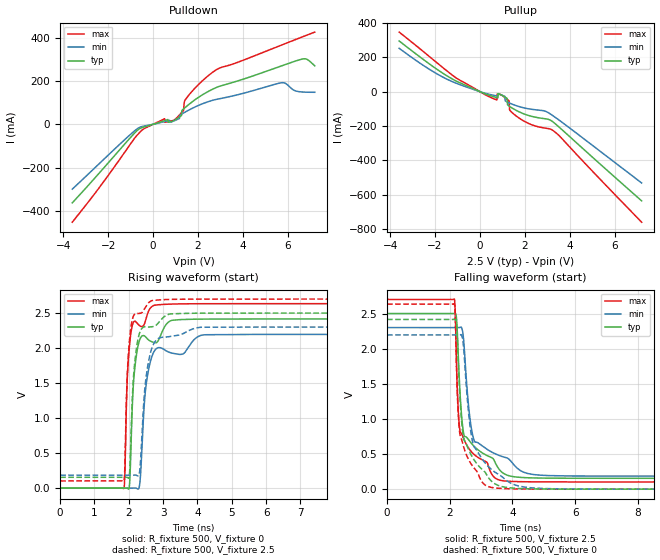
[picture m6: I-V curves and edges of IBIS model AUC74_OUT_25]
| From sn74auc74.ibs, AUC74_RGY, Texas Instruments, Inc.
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[Model]   AUC74_OUT_25
Model_type  Output
Vref =   0
Rref =   500
Cref =   30p
Vmeas =   1.25
| variable   typ   min   max
C_comp   7.89pF   NA   NA
| C_pullup   8.59pF   0.39pF   24.21pF
| C_pulldown   7.03pF   1.93pF   16.23pF
[Temperature Range]   40   100   -40
| Ambient temperature   25   85   -40
[Voltage range]   2.5   2.3   2.7
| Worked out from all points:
|   slope of the pulldown table from 0 to 0.375 V, typ, clamps not added: 30.8 ohm
|   slope of the pullup table from 0 to 0.375 V, typ, clamps not added: 19.1 ohm
|   rising waveform, R_fixture 500, V_fixture 0: 20-80 % time 176ps typ, 234ps min, 134ps max; typ from 0 V to 2.42 V
|   falling waveform, R_fixture 500, V_fixture 2.5: 20-80 % time 487ps typ, 581ps min, 356ps max; typ from 2.5 V to 0.155 V
|   rising waveform, R_fixture 500, V_fixture 2.5: 20-80 % time 177ps typ, 236ps min, 133ps max; typ from 0.154 V to 2.5 V
|   falling waveform, R_fixture 500, V_fixture 0: 20-80 % time 427ps typ, 536ps min, 303ps max; typ from 2.42 V to 0 V
[Pulldown]
| AUC74_OUT_25
|   Voltage   I(typ)   I(min)   I(max)
-3.6V     -363.7mA   -300.2mA   -453.3mA
-675mV    -25.6mA    -18.62mA   -46.23mA
510mV     16.97mA    12.66mA    25.84mA
985mV     20.92mA    18.24mA    23.43mA
1.265V    40.56mA    47.18mA    53.79mA
1.365V    72.41mA    53.05mA    65.54mA
1.395V    75.02mA    54.8mA     105.1mA
1.515V    85.35mA    61.67mA    125.1mA
2.565V    158.2mA    108.6mA    234.2mA
5.74V     271.3mA    192.8mA    367.8mA
6.745V    303.5mA    149.1mA    408.8mA
7.2V      270.9mA    148.4mA    427.2mA
[Pullup]
| AUC74_OUT_25
|   Voltage   I(typ)   I(min)   I(max)
-3.6V     294.9mA    252.3mA    346.6mA
-1.125V   66.08mA    52.58mA    85.6mA
695mV     -32.59mA   -23.56mA   -45.47mA
760mV     -34.84mA   -25.13mA   -47.52mA
770mV     -35.18mA   -25.36mA   -13.19mA
955mV     -19.53mA   -18.91mA   -19.17mA
1.21V     -38.96mA   -59.75mA   -44.51mA
1.29V     -83.38mA   -64.6mA    -53.15mA
1.335V    -87.45mA   -67.22mA   -108.8mA
1.73V     -116.5mA   -86.39mA   -152.4mA
3.31V     -182.1mA   -145.5mA   -231.6mA
7.2V      -635.3mA   -531.1mA   -759.3mA
[Ramp]
| AUC74_OUT_25
| variable   typ   min   max
dV/dt_r   1.46/1.76E-10   1.32/2.34E-10   1.58/1.34E-10
dV/dt_f   1.41/4.89E-10   1.27/5.77E-10   1.56/3.55E-10
R_load = 500
[Rising Waveform]
| AUC74_OUT_25
R_fixture =   500
C_fixture =   0
L_fixture =   0
V_fixture =   0
V_fixture_min = 0
V_fixture_max = 0
|   Time   V(typ)   V(min)   V(max)
0s        11.34nV    33.64nV    1.934nV
1.865ns   136uV      -5.328uV   2.893mV
1.96ns    -2.152mV   -9.831uV   1.612V
2.02ns    45.29mV    -3.751uV   2.035V
2.075ns   778.4mV    105.9uV    2.259V
2.145ns   1.559V     499.7uV    2.376V
2.285ns   2.066V     -10.39mV   2.333V
2.495ns   2.157V     1.438V     2.406V
2.745ns   2.078V     1.958V     2.612V
21.21ns   2.416V     2.195V     2.634V
[Falling Waveform]
| AUC74_OUT_25
R_fixture =   500
C_fixture =   0
L_fixture =   0
V_fixture =   2.5
V_fixture_min = 2.3
V_fixture_max = 2.7
|   Time   V(typ)   V(min)   V(max)
0s        2.5V       2.3V       2.7V
2.15ns    2.502V     2.3V       2.705V
2.225ns   2.384V     2.3V       1.662V
2.335ns   1.328V     2.302V     813.1mV
2.46ns    763.9mV    2.038V     704.9mV
2.61ns    699mV      1.148V     580.7mV
2.765ns   616.3mV    712.5mV    499.1mV
3.585ns   278mV      478.9mV    129.8mV
5.12ns    156.9mV    193.9mV    103.4mV
21.21ns   154.5mV    185.2mV    102.7mV
[Rising Waveform]
| AUC74_OUT_25
R_fixture =   500
C_fixture =   0
L_fixture =   0
V_fixture =   2.5
V_fixture_min = 2.3
V_fixture_max = 2.7
|   Time   V(typ)   V(min)   V(max)
0s        154.5mV    185.2mV    102.6mV
1.865ns   154.6mV    185.2mV    105.4mV
1.96ns    152.4mV    185.2mV    1.669V
2.02ns    200.3mV    185.2mV    2.109V
2.07ns    837.4mV    185.3mV    2.325V
2.14ns    1.611V     185.6mV    2.463V
2.265ns   2.122V     173.6mV    2.494V
2.49ns    2.305V     1.53V      2.585V
2.69ns    2.306V     2.024V     2.68V
21.21ns   2.5V       2.3V       2.7V
[Falling Waveform]
| AUC74_OUT_25
R_fixture =   500
C_fixture =   0
L_fixture =   0
V_fixture =   0
V_fixture_min = 0
V_fixture_max = 0
|   Time   V(typ)   V(min)   V(max)
0s        2.416V     2.195V     2.634V
2.15ns    2.417V     2.195V     2.639V
2.225ns   2.297V     2.195V     1.605V
2.325ns   1.324V     2.196V     782.3mV
2.445ns   720.4mV    2.009V     602mV
2.595ns   571.4mV    1.116V     427.4mV
2.735ns   447.2mV    663.3mV    325.6mV
3.26ns    149.1mV    310mV      32.72mV
4.955ns   2.461mV    9.777mV    730uV
21.21ns   37.98uV    10.72uV    17.21uV
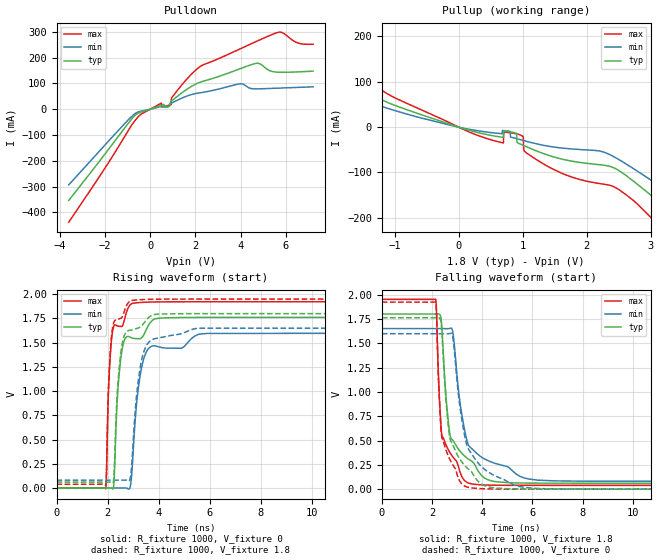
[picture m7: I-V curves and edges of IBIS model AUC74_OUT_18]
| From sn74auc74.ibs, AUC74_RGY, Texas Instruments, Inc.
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[Model]   AUC74_OUT_18
Model_type  Output
Vref =   0
Rref =   1000
Cref =   30p
Vmeas =   0.9
| variable   typ   min   max
C_comp   7.18pF   NA   NA
| C_pullup   7.80pF   2.15pF   21.73pF
| C_pulldown   7.02pF   1.38pF   15.85pF
[Temperature Range]   40   100   -40
| Ambient temperature   25   85   -40
[Voltage range]   1.8   1.65   1.95
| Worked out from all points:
|   slope of the pulldown table from 0 to 0.27 V, typ, clamps not added: 34.3 ohm
|   slope of the pullup table from 0 to 0.27 V, typ, clamps not added: 24.5 ohm
|   rising waveform, R_fixture 1000, V_fixture 0: 20-80 % time 261ps typ, 372ps min, 180ps max; typ from 0 V to 1.76 V
|   falling waveform, R_fixture 1000, V_fixture 1.8: 20-80 % time 624ps typ, 735ps min, 411ps max; typ from 1.8 V to 0.061 V
|   rising waveform, R_fixture 1000, V_fixture 1.8: 20-80 % time 257ps typ, 363ps min, 177ps max; typ from 0.061 V to 1.8 V
|   falling waveform, R_fixture 1000, V_fixture 0: 20-80 % time 574ps typ, 751ps min, 374ps max; typ from 1.76 V to 0 V
[Pulldown]
| AUC74_OUT_18
|   Voltage   I(typ)   I(min)   I(max)
-3.6V     -353.5mA   -293mA     -437.6mA
-665mV    -23.37mA   -16.64mA   -43.39mA
495mV     15.07mA    10.85mA    23.55mA
855mV     12.62mA    20.1mA     15.47mA
925mV     30.87mA    22.97mA    17.67mA
955mV     32.82mA    24.27mA    45.35mA
2.185V    104mA      63.52mA    163.8mA
3.975V    156.9mA    98.42mA    233.9mA
4.69V     177.7mA    78.77mA    262.5mA
5.67V     143.4mA    81.73mA    298.3mA
6.52V     144.7mA    84.53mA    256.8mA
7.2V      147.6mA    86.77mA    251.6mA
[Pullup]
| AUC74_OUT_18
|   Voltage   I(typ)   I(min)   I(max)
-3.6V     269.5mA    225.1mA    320mA
-2.66V    179.8mA    143.7mA    225.6mA
-965mV    46.4mA     35.24mA    62.48mA
460mV     -16.98mA   -11.23mA   -25.96mA
1.005V    -39.82mA   -29.2mA    -20.21mA
1.025V    -41.05mA   -29.97mA   -52.45mA
1.38V     -61mA      -41.47mA   -85.55mA
2.425V    -89.79mA   -65.24mA   -131.4mA
3.15V     -166.9mA   -130.6mA   -219.7mA
3.61V     -220.3mA   -174.9mA   -284mA
3.99V     -264.5mA   -212mA     -336.4mA
7.2V      -633mA     -528.2mA   -768.7mA
[Ramp]
| AUC74_OUT_18
| variable   typ   min   max
dV/dt_r   1.06/2.62E-10   0.97/3.74E-10   1.16/1.80E-10
dV/dt_f   1.04/6.25E-10   0.94/7.33E-10   1.15/4.11E-10
R_load = 1000
[Rising Waveform]
| AUC74_OUT_18
R_fixture =   1000
C_fixture =   0
L_fixture =   0
V_fixture =   0
V_fixture_min = 0
V_fixture_max = 0
|   Time   V(typ)   V(min)   V(max)
0s        8.892nV    30.7nV     1.165nV
1.935ns   -5.775uV   -240.7nV   -8.81mV
2.045ns   160.2uV    -1.184uV   1.051V
2.185ns   -6.12mV    -3.535uV   1.595V
2.25ns    52.3mV     -5.951uV   1.672V
2.53ns    1.358V     49.17uV    1.667V
2.965ns   1.548V     198.7mV    1.904V
3.275ns   1.541V     1.154V     1.914V
3.755ns   1.73V      1.465V     1.92V
21.85ns   1.761V     1.597V     1.922V
[Falling Waveform]
| AUC74_OUT_18
R_fixture =   1000
C_fixture =   0
L_fixture =   0
V_fixture =   1.8
V_fixture_min = 1.65
V_fixture_max = 1.95
|   Time   V(typ)   V(min)   V(max)
0s        1.8V       1.65V      1.95V
2.14ns    1.8V       1.65V      1.951V
2.28ns    1.801V     1.65V      1.014V
2.39ns    1.665V     1.65V      552.7mV
2.55ns    971.1mV    1.649V     459.6mV
2.725ns   547.1mV    1.653V     370.6mV
3.465ns   306.4mV    448mV      61.78mV
4.26ns    93.12mV    289.5mV    42mV
6.23ns    62.05mV    92.48mV    38.91mV
21.85ns   61.09mV    81.11mV    38.7mV
[Rising Waveform]
| AUC74_OUT_18
R_fixture =   1000
C_fixture =   0
L_fixture =   0
V_fixture =   1.8
V_fixture_min = 1.65
V_fixture_max = 1.95
|   Time   V(typ)   V(min)   V(max)
0s        61.05mV    81.09mV    38.68mV
1.935ns   61.04mV    81.09mV    30.05mV
2.045ns   61.2mV     81.09mV    1.084V
2.185ns   55.14mV    81.09mV    1.633V
2.25ns    117.8mV    81.09mV    1.712V
2.515ns   1.382V     81.12mV    1.751V
2.92ns    1.629V     154.6mV    1.933V
3.28ns    1.661V     1.242V     1.943V
3.82ns    1.79V      1.539V     1.948V
21.85ns   1.8V       1.65V      1.95V
[Falling Waveform]
| AUC74_OUT_18
R_fixture =   1000
C_fixture =   0
L_fixture =   0
V_fixture =   0
V_fixture_min = 0
V_fixture_max = 0
|   Time   V(typ)   V(min)   V(max)
0s        1.761V     1.597V     1.922V
2.14ns    1.761V     1.597V     1.923V
2.28ns    1.762V     1.597V     992.3mV
2.385ns   1.642V     1.597V     536.8mV
2.705ns   534mV      1.599V     308.8mV
2.84ns    448.3mV    1.537V     245.4mV
3.09ns    316.6mV    889.5mV    89.99mV
3.375ns   224.1mV    461.7mV    23.74mV
5.825ns   1.374mV    13.93mV    292.9uV
21.85ns   45.12uV    14.45uV    19.62uV
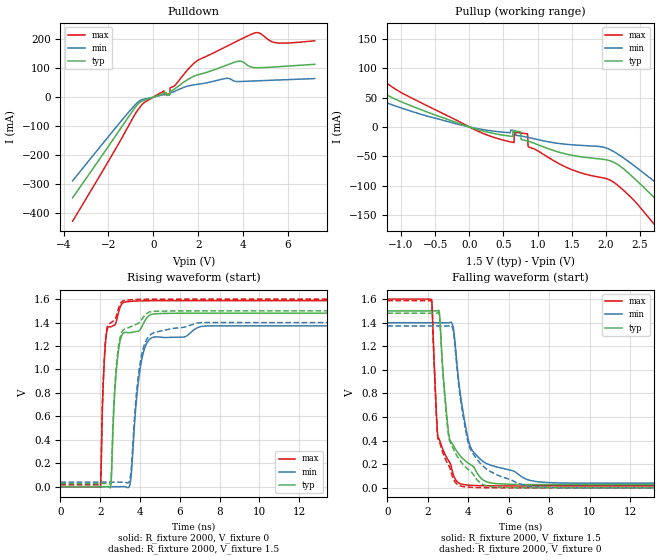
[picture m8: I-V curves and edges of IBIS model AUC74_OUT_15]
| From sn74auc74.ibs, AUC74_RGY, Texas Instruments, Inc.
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[Model]   AUC74_OUT_15
Model_type  Output
Vref =   0
Rref =   2000
Cref =   15p
Vmeas =   0.75
| variable   typ   min   max
C_comp   7.18pF   NA   NA
| C_pullup   6.70pF   0.38pF   19.42pF
| C_pulldown   7.19pF   5.11pF   15.56pF
[Temperature Range]   40   100   -40
| Ambient temperature   25   85   -40
[Voltage range]   1.5   1.4   1.6
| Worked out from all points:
|   slope of the pulldown table from 0 to 0.225 V, typ, clamps not added: 37.2 ohm
|   slope of the pullup table from 0 to 0.225 V, typ, clamps not added: 29.5 ohm
|   rising waveform, R_fixture 2000, V_fixture 0: 20-80 % time 330ps typ, 475ps min, 224ps max; typ from 0 V to 1.48 V
|   falling waveform, R_fixture 2000, V_fixture 1.5: 20-80 % time 720ps typ, 829ps min, 462ps max; typ from 1.5 V to 0.027 V
|   rising waveform, R_fixture 2000, V_fixture 1.5: 20-80 % time 325ps typ, 466ps min, 219ps max; typ from 0.027 V to 1.5 V
|   falling waveform, R_fixture 2000, V_fixture 0: 20-80 % time 690ps typ, 896ps min, 441ps max; typ from 1.48 V to 0 V
[Pulldown]
| AUC74_OUT_15
|   Voltage   I(typ)   I(min)   I(max)
-3.6V     -348.9mA   -290mA     -430.1mA
-665mV    -22.33mA   -15.82mA   -42.01mA
480mV     13.44mA    9.448mA    21.48mA
485mV     13.58mA    9.543mA    7.656mA
735mV     9.012mA    14.01mA    12.18mA
755mV     20.55mA    14.42mA    32.17mA
1.92V     75.6mA     43.88mA    124.2mA
3.275V    111mA      65.24mA    176.1mA
3.81V     124.7mA    54.05mA    196.9mA
4.58V     101.9mA    56.37mA    223.4mA
5.485V    105mA      59.15mA    188.2mA
7.2V      113.8mA    64.38mA    195.3mA
[Pullup]
| AUC74_OUT_15
|   Voltage   I(typ)   I(min)   I(max)
-3.6V     256.9mA    211.2mA    306.3mA
-2.615V   165.5mA    130.5mA    209.1mA
-2.155V   125.2mA    96.54mA    163.9mA
-965mV    41.4mA     31.13mA    56.6mA
395mV     -12mA      -7.71mA    -19.16mA
850mV     -24.02mA   -17.59mA   -11.85mA
870mV     -24.7mA    -18.1mA    -34.17mA
2.095V    -59.3mA    -40.81mA   -92.96mA
2.74V     -124.2mA   -95.87mA   -170.8mA
3.1V      -165.4mA   -129.8mA   -221mA
3.58V     -220.7mA   -176mA     -287mA
7.2V      -633.9mA   -530.4mA   -772.6mA
[Ramp]
| AUC74_OUT_15
| variable   typ   min   max
dV/dt_r   0.89/3.30E-10   0.83/4.80E-10   0.95/2.24E-10
dV/dt_f   0.89/7.17E-10   0.82/8.28E-10   0.95/4.62E-10
R_load = 2000
[Rising Waveform]
| AUC74_OUT_15
R_fixture =   2000
C_fixture =   0
L_fixture =   0
V_fixture =   0
V_fixture_min = 0
V_fixture_max = 0
|   Time   V(typ)   V(min)   V(max)
0s        8.172nV    30.93nV    915.6pV
2.01ns    -2.756uV   26.74nV    -4.418mV
2.23ns    11.34uV    -577.3nV   1.148V
2.515ns   -8.099mV   -3.387uV   1.364V
2.81ns    994.1mV    -11.65uV   1.41V
3.175ns   1.312V     1.03mV     1.571V
3.515ns   1.315V     39mV       1.581V
4.08ns    1.361V     1.08V      1.585V
4.625ns   1.472V     1.274V     1.586V
22.46ns   1.481V     1.373V     1.587V
[Falling Waveform]
| AUC74_OUT_15
R_fixture =   2000
C_fixture =   0
L_fixture =   0
V_fixture =   1.5
V_fixture_min = 1.4
V_fixture_max = 1.6
|   Time   V(typ)   V(min)   V(max)
0s        1.5V       1.4V       1.6V
2.19ns    1.5V       1.4V       1.595V
2.5ns     1.503V     1.4V       426.1mV
2.585ns   1.461V     1.4V       402.9mV
3.035ns   454.6mV    1.4V       227.7mV
3.26ns    360.4mV    1.356V     112.5mV
3.595ns   272.7mV    807.9mV    35.84mV
4.245ns   181.3mV    307mV      20.5mV
7.1ns     27.95mV    61.05mV    16.56mV
22.46ns   27.22mV    38.79mV    16.42mV
[Rising Waveform]
| AUC74_OUT_15
R_fixture =   2000
C_fixture =   0
L_fixture =   0
V_fixture =   1.5
V_fixture_min = 1.4
V_fixture_max = 1.6
|   Time   V(typ)   V(min)   V(max)
0s        27.17mV    38.76mV    16.4mV
2.01ns    27.17mV    38.76mV    12.24mV
2.23ns    27.18mV    38.76mV    1.17V
2.515ns   20.41mV    38.76mV    1.396V
2.8ns     1.008V     38.75mV    1.45V
3.155ns   1.338V     39.59mV    1.586V
3.51ns    1.363V     81.1mV     1.594V
4.075ns   1.424V     1.119V     1.598V
4.695ns   1.496V     1.314V     1.599V
22.46ns   1.5V       1.4V       1.6V
[Falling Waveform]
| AUC74_OUT_15
R_fixture =   2000
C_fixture =   0
L_fixture =   0
V_fixture =   0
V_fixture_min = 0
V_fixture_max = 0
|   Time   V(typ)   V(min)   V(max)
0s        1.481V     1.373V     1.587V
2.19ns    1.481V     1.373V     1.582V
2.495ns   1.483V     1.373V     421.7mV
2.585ns   1.44V      1.373V     387.7mV
3.03ns    438.4mV    1.373V     189.3mV
3.26ns    332.1mV    1.327V     76.8mV
3.57ns    235.9mV    811.4mV    18.99mV
4.225ns   119.6mV    291.1mV    3.964mV
6.73ns    966.7uV    22.62mV    183.9uV
22.46ns   50.05uV    19.78uV    20.95uV
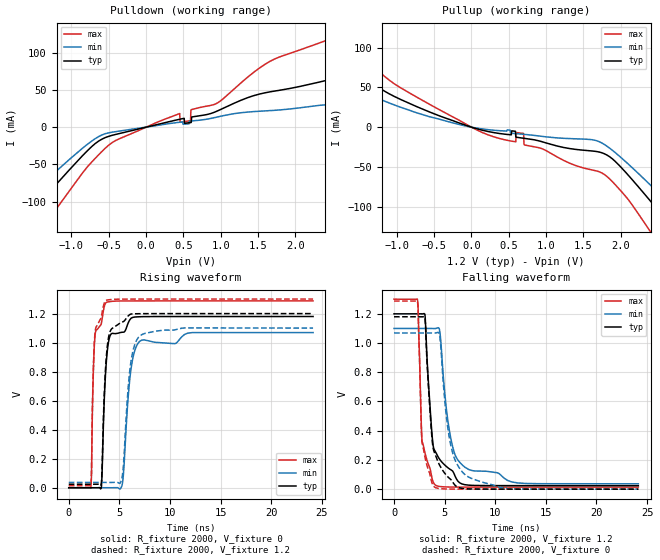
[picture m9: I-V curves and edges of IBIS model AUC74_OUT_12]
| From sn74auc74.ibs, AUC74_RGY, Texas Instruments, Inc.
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[Model]   AUC74_OUT_12
Model_type  Output
Vref =   0
Rref =   2000
Cref =   15p
Vmeas =   0.6
| variable   typ   min   max
C_comp   7.18pF   NA   NA
| C_pullup   6.17pF   1.73pF   16.58pF
| C_pulldown   6.98pF   5.12pF   15.23pF
[Temperature Range]   40   100   -40
| Ambient temperature   25   85   -40
[Voltage range]   1.2   1.1   1.3
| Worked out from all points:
|   slope of the pulldown table from 0 to 0.18 V, typ, clamps not added: 41.8 ohm
|   slope of the pullup table from 0 to 0.18 V, typ, clamps not added: 39.1 ohm
|   rising waveform, R_fixture 2000, V_fixture 0: 20-80 % time 464ps typ, 721ps min, 295ps max; typ from 0 V to 1.18 V
|   falling waveform, R_fixture 2000, V_fixture 1.2: 20-80 % time 850ps typ, 1.21ns min, 533ps max; typ from 1.2 V to 0.024 V
|   rising waveform, R_fixture 2000, V_fixture 1.2: 20-80 % time 452ps typ, 699ps min, 288ps max; typ from 0.024 V to 1.2 V
|   falling waveform, R_fixture 2000, V_fixture 0: 20-80 % time 863ps typ, 1.21ns min, 501ps max; typ from 1.18 V to 0 V
[Pulldown]
| AUC74_OUT_12
|   Voltage   I(typ)   I(min)   I(max)
-3.6V     -344.2mA   -286.4mA   -423.7mA
-2.15V    -182.8mA   -147.6mA   -235.5mA
-1.805V   -144.2mA   -114.9mA   -190.3mA
-1.485V   -108.4mA   -85mA      -147.9mA
-540mV    -13.77mA   -8.637mA   -27.68mA
450mV     10.61mA    6.629mA    18.27mA
590mV     6.038mA    8.092mA    8.62mA
605mV     6.519mA    8.238mA    23.43mA
960mV     21.97mA    13.76mA    32.78mA
1.66V     47.45mA    22.23mA    88.51mA
2.925V    73.64mA    26.98mA    135.6mA
7.2V      80.49mA    37.89mA    151.4mA
[Pullup]
| AUC74_OUT_12
|   Voltage   I(typ)   I(min)   I(max)
-3.6V     240.8mA    114.9mA    293.4mA
-2.4V     135.2mA    99.36mA    177.2mA
-1.885V   93.67mA    68.26mA    128.1mA
-1.03V    38.54mA    27.9mA     54.4mA
30mV      -869.7uA   -515.3uA   -1.516mA
700mV     -14.01mA   -9.053mA   -8.046mA
715mV     -14.2mA    -9.18mA    -22.56mA
1.785V    -33.67mA   -22.04mA   -59.85mA
2.445V    -98.21mA   -77.14mA   -138.1mA
2.62V     -117.9mA   -93.3mA    -162.3mA
3.06V     -167.9mA   -134.8mA   -222.7mA
7.2V      -637.1mA   -536.9mA   -775.9mA
[Ramp]
| AUC74_OUT_12
| variable   typ   min   max
dV/dt_r   0.71/4.68E-10   0.65/7.26E-10   0.77/2.95E-10
dV/dt_f   0.71/8.47E-10   0.64/1.21E-09   0.77/5.31E-10
R_load = 2000
[Rising Waveform]
| AUC74_OUT_12
R_fixture =   2000
C_fixture =   0
L_fixture =   0
V_fixture =   0
V_fixture_min = 0
V_fixture_max = 0
|   Time   V(typ)   V(min)   V(max)
0s        7.653nV    32.85nV    737.2pV
2.175ns   -205.2nV   91.82nV    -3.829mV
2.58ns    -6.4uV     -373.7nV   1.035V
3.23ns    6.632mV    -408nV     1.135V
3.675ns   828.5mV    -5.054uV   1.274V
4.1ns     1.05V      -22.23uV   1.283V
5.26ns    1.071V     13.56mV    1.287V
6.11ns    1.164V     795.9mV    1.287V
7.04ns    1.178V     1.01V      1.287V
24.14ns   1.18V      1.069V     1.287V
[Falling Waveform]
| AUC74_OUT_12
R_fixture =   2000
C_fixture =   0
L_fixture =   0
V_fixture =   1.2
V_fixture_min = 1.1
V_fixture_max = 1.3
|   Time   V(typ)   V(min)   V(max)
0s        1.2V       1.1V       1.3V
2.305ns   1.2V       1.1V       1.301V
2.77ns    1.2V       1.1V       330.7mV
3.055ns   1.196V     1.1V       249.8mV
3.7ns     423.2mV    1.1V       93.59mV
4.08ns    257.4mV    1.099V     28.2mV
4.53ns    202.4mV    1.075V     18.42mV
5.68ns    129.8mV    324.9mV    14.54mV
6.99ns    30.73mV    150.9mV    14.08mV
24.14ns   24.04mV    36.67mV    13.88mV
[Rising Waveform]
| AUC74_OUT_12
R_fixture =   2000
C_fixture =   0
L_fixture =   0
V_fixture =   1.2
V_fixture_min = 1.1
V_fixture_max = 1.3
|   Time   V(typ)   V(min)   V(max)
0s        23.98mV    36.62mV    13.86mV
2.175ns   23.98mV    36.62mV    10.1mV
2.575ns   23.97mV    36.62mV    1.051V
3.225ns   32.78mV    36.62mV    1.179V
3.65ns    838.4mV    36.62mV    1.289V
4.075ns   1.075V     36.61mV    1.296V
5.255ns   1.141V     65.6mV     1.3V
6.09ns    1.195V     840.9mV    1.3V
7.085ns   1.199V     1.049V     1.3V
24.14ns   1.2V       1.1V       1.3V
[Falling Waveform]
| AUC74_OUT_12
R_fixture =   2000
C_fixture =   0
L_fixture =   0
V_fixture =   0
V_fixture_min = 0
V_fixture_max = 0
|   Time   V(typ)   V(min)   V(max)
0s        1.18V      1.069V     1.287V
2.305ns   1.18V      1.069V     1.288V
2.76ns    1.179V     1.069V     324.6mV
3.06ns    1.172V     1.069V     219.5mV
3.63ns    458.4mV    1.069V     74.94mV
3.99ns    251.5mV    1.068V     15.27mV
4.52ns    162.5mV    1.045V     4.021mV
5.635ns   64.59mV    291.9mV    654.6uV
7.09ns    3.028mV    95.37mV    195.2uV
24.14ns   56.02uV    33.13uV    20.75uV
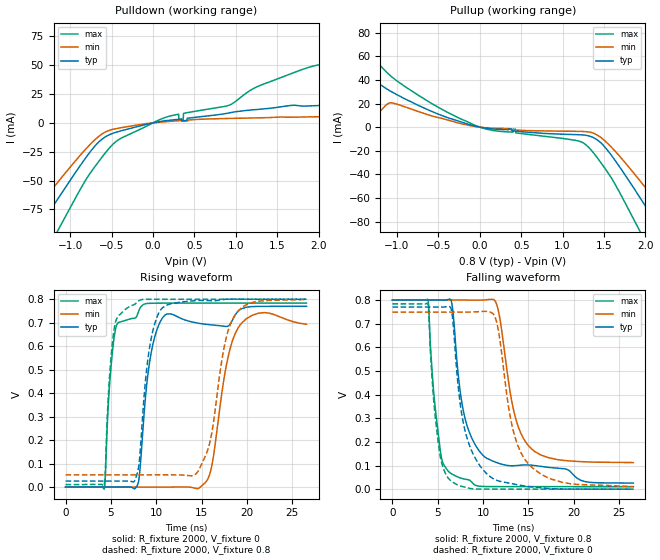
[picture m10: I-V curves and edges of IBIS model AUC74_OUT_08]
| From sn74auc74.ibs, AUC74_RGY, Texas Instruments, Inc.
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[Model]   AUC74_OUT_08
Model_type  Output
Vref =   0
Rref =   2000
Cref =   15p
Vmeas =   0.4
| variable   typ   min   max
C_comp   7.18pF   NA   NA
| C_pullup   5.41pF   2.75pF   7.31pF
| C_pulldown   6.51pF   5.90pF   6.86pF
[Temperature Range]   40   100   -40
| Ambient temperature   25   85   -40
[Voltage range]   0.8   0.8   0.8
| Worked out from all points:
|   slope of the pulldown table from 0 to 0.12 V, typ, clamps not added: 76.8 ohm
|   slope of the pullup table from 0 to 0.12 V, typ, clamps not added: 92.9 ohm
|   rising waveform, R_fixture 2000, V_fixture 0: 20-80 % time 1.31ns typ, 1.59ns min, 829ps max; typ from 0 V to 0.77 V
|   falling waveform, R_fixture 2000, V_fixture 0.8: 20-80 % time 2.34ns typ, 1.94ns min, 1.12ns max; typ from 0.8 V to 0.026 V
|   rising waveform, R_fixture 2000, V_fixture 0.8: 20-80 % time 1.22ns typ, 1.83ns min, 771ps max; typ from 0.025 V to 0.8 V
|   falling waveform, R_fixture 2000, V_fixture 0: 20-80 % time 1.97ns typ, 2.17ns min, 1.06ns max; typ from 0.77 V to 0 V
[Pulldown]
| AUC74_OUT_08
|   Voltage   I(typ)   I(min)   I(max)
-3.6V     -337.8mA   -282.7mA   -412.9mA
-1.64V    -120mA     -96.2mA    -158.2mA
-1.38V    -91.24mA   -72.24mA   -124mA
-1.16V    -67.12mA   -52.4mA    -94.87mA
-645mV    -15.96mA   -11.19mA   -32.55mA
-440mV    -8mA       -4.926mA   -15.86mA
-90mV     -1.494mA   -794.3uA   -3.292mA
920mV     8.612mA    3.848mA    15.28mA
1.255V    11.59mA    4.33mA     31.21mA
1.975V    14.94mA    5.284mA    49.84mA
2.355V    16.24mA    5.742mA    46.35mA
7.2V      33.47mA    12.46mA    83.24mA
[Pullup]
| AUC74_OUT_08
|   Voltage   I(typ)   I(min)   I(max)
-3.6V     116.9mA    22mA       233.8mA
-2.915V   84.58mA    23.73mA    197.7mA
-2.11V    49.42mA    22.96mA    129mA
-1.6V     50.73mA    12.09mA    84.46mA
-1.305V   41.1mA     8.572mA    60.06mA
-1.065V   29.95mA    20.61mA    42.74mA
-280mV    5.689mA    3.931mA    8.664mA
1.255V    -6.679mA   -3.706mA   -13.6mA
1.515V    -17.25mA   -11.86mA   -35.29mA
1.975V    -64.13mA   -49.02mA   -93.8mA
2.38V     -108.9mA   -85.69mA   -148.3mA
7.2V      -648.2mA   -549.1mA   -783.5mA
[Ramp]
| AUC74_OUT_08
| variable   typ   min   max
dV/dt_r   0.47/1.31E-09   0.45/1.82E-09   0.48/8.31E-10
dV/dt_f   0.47/2.33E-09   0.41/1.94E-09   0.48/1.12E-09
R_load = 2000
[Rising Waveform]
| AUC74_OUT_08
R_fixture =   2000
C_fixture =   0
L_fixture =   0
V_fixture =   0
V_fixture_min = 0
V_fixture_max = 0
|   Time   V(typ)   V(min)   V(max)
0s        9.41nV     53.68nV    554pV
4.255ns   -91.79nV   262.8nV    -8.966mV
4.985ns   -1.373uV   104.8nV    500.6mV
5.82ns    -15.23uV   3.703nV    700.7mV
8ns       15.86mV    -980.4nV   742mV
9.29ns    537.7mV    -3.798uV   782.6mV
10.88ns   729.9mV    -6.103uV   783.4mV
15.73ns   692.2mV    36.86mV    783.7mV
19.42ns   759.6mV    698.4mV    783.7mV
26.58ns   769.9mV    693.5mV    783.7mV
[Falling Waveform]
| AUC74_OUT_08
R_fixture =   2000
C_fixture =   0
L_fixture =   0
V_fixture =   0.8
V_fixture_min = 0.8
V_fixture_max = 0.8
|   Time   V(typ)   V(min)   V(max)
0s        800mV      800mV      800mV
3.94ns    800mV      800mV      797.3mV
5.2ns     799.7mV    800mV      187.3mV
6.345ns   803.9mV    800mV      69.5mV
7.86ns    323.6mV    799.9mV    43.5mV
9.985ns   143.1mV    799.8mV    11.56mV
11.53ns   112mV      777.3mV    10.83mV
13.39ns   99.13mV    330.7mV    10.72mV
15.12ns   102.1mV    178.9mV    10.69mV
26.58ns   25.76mV    112.6mV    10.63mV
[Rising Waveform]
| AUC74_OUT_08
R_fixture =   2000
C_fixture =   0
L_fixture =   0
V_fixture =   0.8
V_fixture_min = 0.8
V_fixture_max = 0.8
|   Time   V(typ)   V(min)   V(max)
0s        25.46mV    52.07mV    10.6mV
4.255ns   25.46mV    52.07mV    6.184mV
5.27ns    25.46mV    52.07mV    649.3mV
6.69ns    25.63mV    52.07mV    759.9mV
7.98ns    68.96mV    52.07mV    790.9mV
9.195ns   577.4mV    52.07mV    799.8mV
10.66ns   763mV      52.12mV    799.8mV
15.34ns   794.9mV    125.8mV    799.9mV
18.94ns   800.6mV    745.8mV    799.9mV
26.58ns   799.9mV    798.9mV    800mV
[Falling Waveform]
| AUC74_OUT_08
R_fixture =   2000
C_fixture =   0
L_fixture =   0
V_fixture =   0
V_fixture_min = 0
V_fixture_max = 0
|   Time   V(typ)   V(min)   V(max)
0s        770mV      748.6mV    783.8mV
3.92ns    770mV      748.6mV    781.7mV
5.075ns   770mV      748.6mV    189.8mV
6.5ns     758.6mV    748.6mV    33.88mV
7.875ns   269.4mV    748.7mV    9.666mV
10.33ns   67.93mV    752.1mV    262.9uV
11.46ns   38.03mV    711.3mV    163uV
13.18ns   23.31mV    271.1mV    107.2uV
14.9ns    11.85mV    111.4mV    80.42uV
26.58ns   136.5uV    10.34mV    29.1uV
